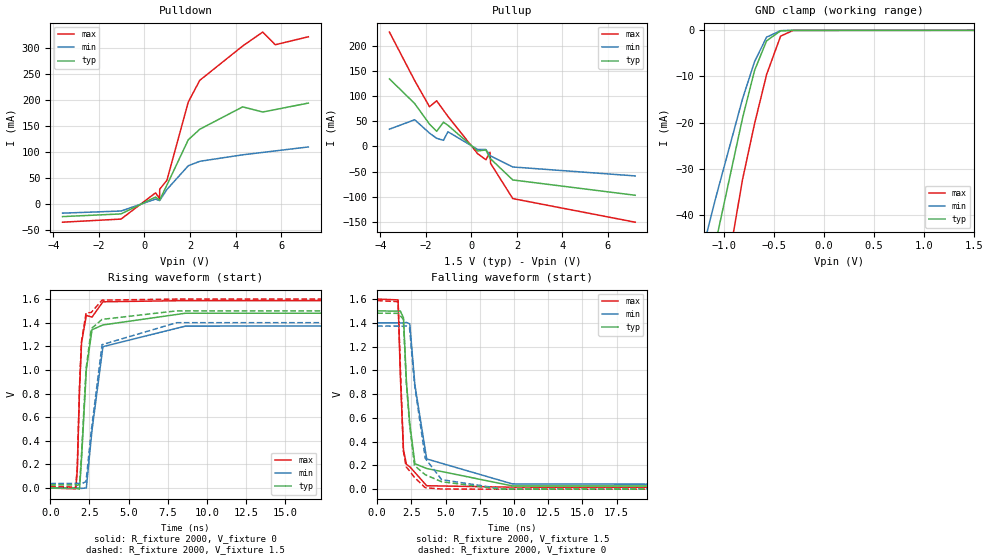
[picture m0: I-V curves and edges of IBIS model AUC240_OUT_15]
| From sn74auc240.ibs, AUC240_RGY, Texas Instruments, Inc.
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[Model]   AUC240_OUT_15
Model_type  3-state
Enable   Active-Low
Vref =   0
Rref =   2000
Cref =   15p
Vmeas =   0.75
| variable   typ   min   max
C_comp   5.73pF   5.19pF   6.05pF
| C_pullup   5.15pF   0.68pF   12.48pF
| C_pulldown   6.58pF   5.58pF   11.69pF
| C_tri-state   5.73pF   5.19pF   6.05pF
[Temperature Range]   40   100   -40
| Ambient temperature   25   85   -40
[Voltage range]   1.5   1.4   1.6
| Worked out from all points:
|   slope of the pulldown table from 0 to 0.225 V, typ, clamps not added: 37.2 ohm
|   slope of the pullup table from 0 to 0.225 V, typ, clamps not added: 29.7 ohm
|   GND clamp passes 1 mA (typ) near -0.53 V on its own axis
|   rising waveform, R_fixture 2000, V_fixture 0: 20-80 % time 420ps typ, 646ps min, 261ps max; typ from 0 V to 1.48 V
|   falling waveform, R_fixture 2000, V_fixture 1.5: 20-80 % time 551ps typ, 877ps min, 302ps max; typ from 1.5 V to 0.027 V
|   rising waveform, R_fixture 2000, V_fixture 1.5: 20-80 % time 416ps typ, 640ps min, 257ps max; typ from 0.027 V to 1.5 V
|   falling waveform, R_fixture 2000, V_fixture 0: 20-80 % time 548ps typ, 874ps min, 298ps max; typ from 1.48 V to 0 V
[GND Clamp]
| AUC240_OUT_15
|   Voltage   I(typ)   I(min)   I(max)
-3.6V     -319.1mA   -267.5mA   -389.1mA
-1.465V   -86.56mA   -69.57mA   -115.8mA
-1.33V    -72.07mA   -57.62mA   -98.32mA
-1.29V    -67.79mA   -54.11mA   -93.12mA
-1.125V   -50.33mA   -39.87mA   -71.67mA
-1.075V   -45.1mA    -35.64mA   -65.18mA
-815mV    -18.99mA   -14.82mA   -32.28mA
-695mV    -8.67mA    -6.76mA    -20.21mA
-575mV    -2.27mA    -1.475mA   -9.572mA
-435mV    -119.4uA   -67.11uA   -1.249mA
-310mV    -3.104uA   -3.768uA   -25uA
1.5V      550.3pA    10.34nA    531.3pA
[Pulldown]
| AUC240_OUT_15
|   Voltage   I(typ)   I(min)   I(max)
-3.6V     -23.87mA   -17.26mA   -34.61mA
-1.03V    -18.71mA   -13.15mA   -28.63mA
485mV     13.68mA    9.737mA    21.72mA
660mV     8.179mA    6.945mA    10.96mA
670mV     8.318mA    7.09mA     28.79mA
985mV     36.64mA    28.23mA    45.9mA
1.925V    123.7mA    73.77mA    196.2mA
2.43V     143.9mA    82.33mA    237.9mA
4.315V    186.9mA    94.81mA    303.8mA
5.195V    177mA      99.37mA    330.5mA
5.745V    181.6mA    102.3mA    306.2mA
7.2V      194.2mA    109.9mA    321.5mA
[Pullup]
| AUC240_OUT_15
|   Voltage   I(typ)   I(min)   I(max)
-3.6V     133.9mA    34.19mA    226.6mA
-2.49V    84.93mA    52.91mA    130.4mA
-1.84V    44.23mA    26.42mA    78.7mA
-1.525V   29.94mA    16.1mA     90.45mA
-1.225V   48.04mA    12.14mA    71.67mA
-1.03V    41.9mA     29.08mA    59.59mA
275mV     -9.031mA   -5.857mA   -14.38mA
640mV     -6.934mA   -6.164mA   -26.37mA
820mV     -23.64mA   -17.98mA   -11.49mA
845mV     -24.58mA   -18.83mA   -33.67mA
1.82V     -66.39mA   -40.69mA   -103.3mA
7.2V      -96.74mA   -58.4mA    -150.1mA
[Ramp]
| AUC240_OUT_15
| variable   typ   min   max
dV/dt_r   0.90/4.24E-10   0.83/6.52E-10   0.96/2.63E-10
dV/dt_f   0.89/5.52E-10   0.82/8.81E-10   0.95/3.04E-10
R_load = 2000
[Rising Waveform]
| AUC240_OUT_15
R_fixture =   2000
C_fixture =   0
L_fixture =   0
V_fixture =   0
V_fixture_min = 0
V_fixture_max = 0
|   Time   V(typ)   V(min)   V(max)
0s        9.799nV    37.61nV    995.6pV
1.63ns    348uV      750uV      -6.097mV
1.725ns   -4.351mV   989uV      146.6mV
1.87ns    -9.064mV   990.7uV    839.5mV
2ns       254.7mV    -2.694mV   1.232V
2.305ns   1.003V     1.676mV    1.462V
2.665ns   1.34V      487.4mV    1.447V
3.365ns   1.381V     1.197V     1.577V
8.64ns    1.48V      1.371V     1.587V
34.99ns   1.481V     1.373V     1.587V
[Falling Waveform]
| AUC240_OUT_15
R_fixture =   2000
C_fixture =   0
L_fixture =   0
V_fixture =   1.5
V_fixture_min = 1.4
V_fixture_max = 1.6
|   Time   V(typ)   V(min)   V(max)
0s        1.5V       1.4V       1.6V
1.53ns    1.499V     1.4V       1.593V
1.69ns    1.5V       1.399V     969.3mV
1.925ns   1.442V     1.399V     328mV
2.14ns    901.9mV    1.403V     209.2mV
2.385ns   550mV      1.391V     188.1mV
2.76ns    213.9mV    876.1mV    140.6mV
3.62ns    174mV      254.4mV    28.93mV
9.88ns    27.55mV    44.3mV     16.5mV
34.99ns   27.21mV    38.76mV    16.42mV
[Rising Waveform]
| AUC240_OUT_15
R_fixture =   2000
C_fixture =   0
L_fixture =   0
V_fixture =   1.5
V_fixture_min = 1.4
V_fixture_max = 1.6
|   Time   V(typ)   V(min)   V(max)
0s        27.17mV    38.75mV    16.4mV
1.625ns   27.61mV    39.42mV    7.834mV
1.725ns   23.28mV    39.64mV    173.2mV
1.875ns   32.96mV    39.57mV    885.5mV
1.99ns    268.8mV    36.84mV    1.236V
2.285ns   1.005V     54.82mV    1.482V
2.62ns    1.349V     484.3mV    1.487V
3.31ns    1.428V     1.214V     1.591V
8.07ns    1.5V       1.4V       1.6V
34.99ns   1.5V       1.4V       1.6V
[Falling Waveform]
| AUC240_OUT_15
R_fixture =   2000
C_fixture =   0
L_fixture =   0
V_fixture =   0
V_fixture_min = 0
V_fixture_max = 0
|   Time   V(typ)   V(min)   V(max)
0s        1.481V     1.373V     1.587V
1.53ns    1.48V      1.372V     1.578V
1.915ns   1.43V      1.371V     322.1mV
2.125ns   912.7mV    1.374V     186.9mV
2.365ns   549.6mV    1.361V     154.3mV
2.73ns    198.6mV    885.2mV    99.08mV
3.515ns   121.6mV    259.4mV    12.24mV
4.715ns   62.34mV    79.85mV    1.182mV
8.97ns    445.1uV    6.101mV    117uV
34.99ns   39.56uV    5.093uV    17.41uV
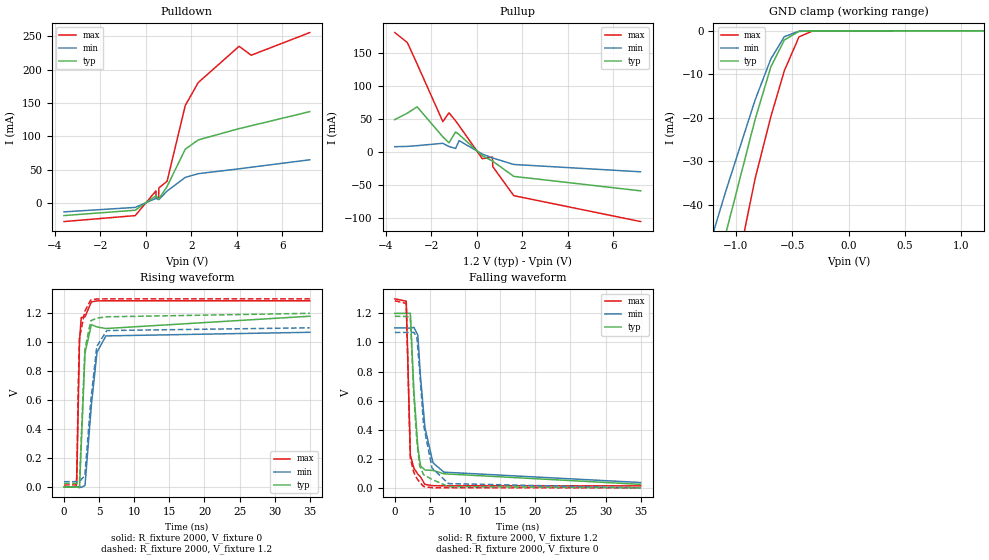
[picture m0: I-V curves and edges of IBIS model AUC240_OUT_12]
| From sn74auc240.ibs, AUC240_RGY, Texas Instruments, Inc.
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[Model]   AUC240_OUT_12
Model_type  3-state
Enable   Active-Low
Vref =   0
Rref =   2000
Cref =   15p
Vmeas =   0.6
| variable   typ   min   max
C_comp   5.84pF   5.33pF   6.15pF
| C_pullup   5.07pF   0.36pF   9.98pF
| C_pulldown   6.41pF   5.70pF   7.44pF
| C_tri-state   5.84pF   5.33pF   6.15pF
[Temperature Range]   40   100   -40
| Ambient temperature   25   85   -40
[Voltage range]   1.2   1.1   1.3
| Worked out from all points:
|   slope of the pulldown table from 0 to 0.18 V, typ, clamps not added: 42.1 ohm
|   slope of the pullup table from 0 to 0.18 V, typ, clamps not added: 38.3 ohm
|   GND clamp passes 1 mA (typ) near -0.53 V on its own axis
|   rising waveform, R_fixture 2000, V_fixture 0: 20-80 % time 597ps typ, 1.03ns min, 338ps max; typ from 0 V to 1.18 V
|   falling waveform, R_fixture 2000, V_fixture 1.2: 20-80 % time 874ps typ, 1.39ns min, 427ps max; typ from 1.2 V to 0.024 V
|   rising waveform, R_fixture 2000, V_fixture 1.2: 20-80 % time 590ps typ, 1.03ns min, 330ps max; typ from 0.024 V to 1.2 V
|   falling waveform, R_fixture 2000, V_fixture 0: 20-80 % time 864ps typ, 1.31ns min, 422ps max; typ from 1.18 V to 0 V
[GND Clamp]
| AUC240_OUT_12
|   Voltage   I(typ)   I(min)   I(max)
-3.6V     -319.1mA   -267.5mA   -389.1mA
-1.46V    -86.02mA   -69.12mA   -115.2mA
-1.415V   -81.18mA   -65.12mA   -109.4mA
-1.285V   -67.26mA   -53.68mA   -92.47mA
-1.12V    -49.8mA    -39.44mA   -71.02mA
-1.085V   -46.14mA   -36.48mA   -66.48mA
-830mV    -20.41mA   -15.93mA   -34.03mA
-690mV    -8.305mA   -6.469mA   -19.75mA
-570mV    -2.106mA   -1.347mA   -9.166mA
-440mV    -136.2uA   -75.22uA   -1.399mA
-320mV    -4.216uA   -4.87uA    -36.5uA
1.2V      442.5pA    10.22nA    378.9pA
[Pulldown]
| AUC240_OUT_12
|   Voltage   I(typ)   I(min)   I(max)
-3.6V     -19.18mA   -13.63mA   -28.17mA
-470mV    -11.13mA   -6.91mA    -19.23mA
440mV     10.48mA    6.706mA    17.92mA
445mV     10.59mA    6.769mA    6.318mA
560mV     5.857mA    4.698mA    8.209mA
570mV     5.97mA     4.785mA    22.41mA
930mV     24.61mA    17.66mA    32.37mA
1.73V     80.53mA    38.18mA    146.2mA
2.3V      94.46mA    43.74mA    180.6mA
4.095V    111.4mA    51.05mA    235mA
4.625V    115.7mA    53.39mA    221.6mA
7.2V      136.9mA    64.6mA     255.6mA
[Pullup]
| AUC240_OUT_12
|   Voltage   I(typ)   I(min)   I(max)
-3.6V     48.8mA     7.73mA     180.5mA
-3.05V    58.5mA     8.2mA      165.4mA
-2.62V    68.11mA    9.305mA    132.9mA
-1.49V    22.6mA     12.87mA    45.69mA
-1.22V    13.65mA    7.955mA    59.11mA
-930mV    30.05mA    5.089mA    46.94mA
-775mV    26.1mA     16.83mA    39.5mA
245mV     -5.916mA   -3.381mA   -10.43mA
690mV     -14.05mA   -9.318mA   -7.997mA
705mV     -14.25mA   -9.471mA   -22.45mA
1.625V    -37.2mA    -19.16mA   -66.38mA
7.2V      -59.1mA    -30.27mA   -105.6mA
[Ramp]
| AUC240_OUT_12
| variable   typ   min   max
dV/dt_r   0.72/6.03E-10   0.65/1.04E-09   0.78/3.41E-10
dV/dt_f   0.71/8.77E-10   0.64/1.39E-09   0.77/4.32E-10
R_load = 2000
[Rising Waveform]
| AUC240_OUT_12
R_fixture =   2000
C_fixture =   0
L_fixture =   0
V_fixture =   0
V_fixture_min = 0
V_fixture_max = 0
|   Time   V(typ)   V(min)   V(max)
0s        9.189nV    39.93nV    791.2pV
1.75ns    708.7uV    366uV      924.3uV
1.825ns   798.9uV    495uV      60.17mV
2.21ns    -6.059mV   1.444mV    1.01V
2.46ns    292.5mV    -3.387mV   1.17V
2.995ns   927.4mV    10.9mV     1.177V
3.9ns     1.122V     565.9mV    1.279V
4.7ns     1.106V     931.1mV    1.286V
5.97ns    1.095V     1.044V     1.287V
34.99ns   1.18V      1.069V     1.287V
[Falling Waveform]
| AUC240_OUT_12
R_fixture =   2000
C_fixture =   0
L_fixture =   0
V_fixture =   1.2
V_fixture_min = 1.1
V_fixture_max = 1.3
|   Time   V(typ)   V(min)   V(max)
0s        1.2V       1.1V       1.3V
1.625ns   1.2V       1.1V       1.284V
2.21ns    1.201V     1.099V     224.4mV
2.72ns    657.1mV    1.104V     135.1mV
3.275ns   283.2mV    1.05V      94.28mV
3.655ns   150.9mV    765.8mV    75.21mV
4.285ns   122.8mV    415.8mV    23.41mV
5.43ns    120.1mV    172.2mV    14.94mV
6.99ns    96.77mV    108mV      14.16mV
34.99ns   24.03mV    36.64mV    13.88mV
[Rising Waveform]
| AUC240_OUT_12
R_fixture =   2000
C_fixture =   0
L_fixture =   0
V_fixture =   1.2
V_fixture_min = 1.1
V_fixture_max = 1.3
|   Time   V(typ)   V(min)   V(max)
0s        23.98mV    36.61mV    13.86mV
1.745ns   24.6mV     36.92mV    14.73mV
1.825ns   24.68mV    37.03mV    83.81mV
2.025ns   19.36mV    37.36mV    683.6mV
2.205ns   33.36mV    37.7mV     1.03V
2.97ns    949.2mV    78.55mV    1.215V
3.82ns    1.149V     596mV      1.293V
4.665ns   1.167V     972mV      1.299V
6.095ns   1.176V     1.081V     1.3V
34.99ns   1.2V       1.1V       1.3V
[Falling Waveform]
| AUC240_OUT_12
R_fixture =   2000
C_fixture =   0
L_fixture =   0
V_fixture =   0
V_fixture_min = 0
V_fixture_max = 0
|   Time   V(typ)   V(min)   V(max)
0s        1.18V      1.069V     1.287V
1.625ns   1.179V     1.069V     1.269V
2.21ns    1.174V     1.068V     203.6mV
2.7ns     636.7mV    1.07V      106.9mV
3.14ns    320.6mV    1.036V     64.66mV
3.535ns   152.1mV    804.4mV    39.08mV
4.09ns    90.67mV    431.9mV    9.619mV
5.3ns     57.97mV    136mV      954.3uV
7.63ns    8.494mV    29.25mV    204uV
34.99ns   50.42uV    12.36uV    18.72uV
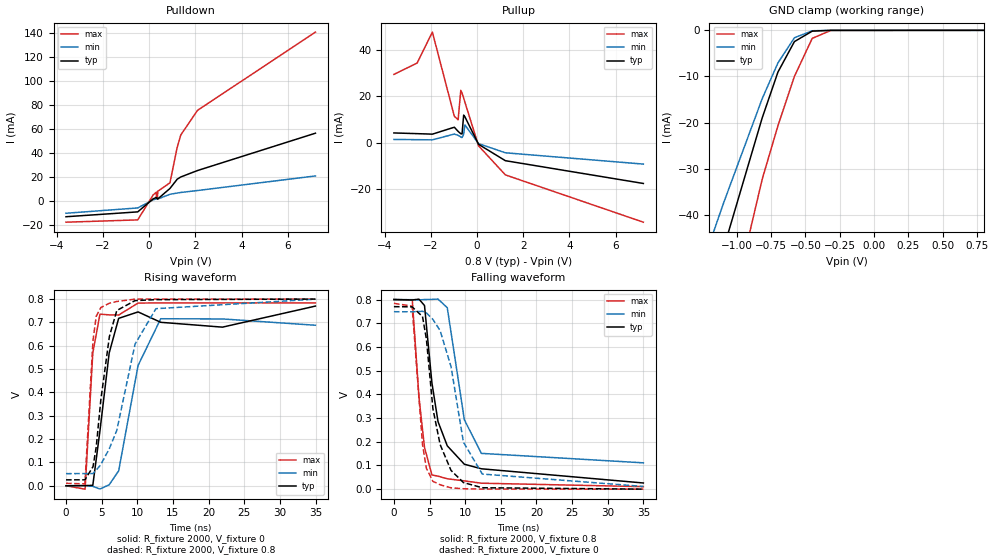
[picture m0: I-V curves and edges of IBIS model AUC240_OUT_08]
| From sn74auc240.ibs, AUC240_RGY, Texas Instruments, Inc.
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[Model]   AUC240_OUT_08
Model_type  3-state
Enable   Active-Low
Vref =   0
Rref =   2000
Cref =   15p
Vmeas =   0.4
| variable   typ   min   max
C_comp   5.94pF   5.47pF   6.22pF
| C_pullup   6.11pF   1.57pF   8.48pF
| C_pulldown   6.55pF   5.99pF   7.01pF
| C_tri-state   5.94pF   5.47pF   6.22pF
[Temperature Range]   40   100   -40
| Ambient temperature   25   85   -40
[Voltage range]   0.8   0.8   0.8
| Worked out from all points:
|   slope of the pulldown table from 0 to 0.12 V, typ, clamps not added: 77.5 ohm
|   slope of the pullup table from 0 to 0.12 V, typ, clamps not added: 92.9 ohm
|   GND clamp passes 1 mA (typ) near -0.53 V on its own axis
|   rising waveform, R_fixture 2000, V_fixture 0: 20-80 % time 1.81ns typ, 2.48ns min, 953ps max; typ from 0 V to 0.77 V
|   falling waveform, R_fixture 2000, V_fixture 0.8: 20-80 % time 2.72ns typ, 2.13ns min, 1.39ns max; typ from 0.8 V to 0.026 V
|   rising waveform, R_fixture 2000, V_fixture 0.8: 20-80 % time 1.83ns typ, 3.54ns min, 902ps max; typ from 0.025 V to 0.8 V
|   falling waveform, R_fixture 2000, V_fixture 0: 20-80 % time 2.24ns typ, 2.81ns min, 1.25ns max; typ from 0.77 V to 0 V
[GND Clamp]
| AUC240_OUT_08
|   Voltage   I(typ)   I(min)   I(max)
-3.6V     -319.1mA   -267.5mA   -389.1mA
-1.475V   -87.64mA   -70.46mA   -117.1mA
-1.34V    -73.14mA   -58.5mA    -99.62mA
-1.295V   -68.33mA   -54.55mA   -93.77mA
-1.125V   -50.33mA   -39.87mA   -71.67mA
-1.09V    -46.66mA   -36.9mA    -67.13mA
-815mV    -18.99mA   -14.82mA   -32.28mA
-700mV    -9.043mA   -7.055mA   -20.67mA
-580mV    -2.441mA   -1.611mA   -9.983mA
-450mV    -176.4uA   -94.71uA   -1.735mA
-315mV    -3.617uA   -4.287uA   -30.24uA
800mV     320.2pA    582.3pA    244.9pA
[Pulldown]
| AUC240_OUT_08
|   Voltage   I(typ)   I(min)   I(max)
-3.6V     -12.84mA   -9.953mA   -17.38mA
-495mV    -8.803mA   -5.523mA   -15.47mA
175mV     2.059mA    1.185mA    5.31mA
310mV     3.174mA    2.053mA    7.502mA
315mV     3.217mA    2.087mA    2.47mA
365mV     1.856mA    1.796mA    2.807mA
370mV     1.894mA    1.829mA    8.27mA
900mV     10.66mA    5.825mA    15.37mA
1.215V    18.37mA    6.848mA    44.91mA
1.37V     20.23mA    7.332mA    55.15mA
2.09V     25.55mA    8.946mA    75.56mA
7.2V      56.63mA    21.09mA    140.7mA
[Pullup]
| AUC240_OUT_08
|   Voltage   I(typ)   I(min)   I(max)
-3.6V     4.13mA     1.333mA    29.34mA
-2.595V   3.829mA    1.231mA    34.24mA
-1.935V   3.609mA    1.155mA    47.57mA
-985mV    6.593mA    3.652mA    11.35mA
-820mV    4.807mA    3.079mA    9.795mA
-705mV    3.788mA    2.41mA     22.46mA
-650mV    3.702mA    2.149mA    21.3mA
-580mV    11.83mA    3.56mA     19.16mA
-530mV    11.15mA    7.583mA    17.47mA
65mV      -779.5uA   -459.6uA   -1.427mA
1.225V    -7.819mA   -4.418mA   -13.93mA
7.2V      -17.63mA   -9.285mA   -34.31mA
[Ramp]
| AUC240_OUT_08
| variable   typ   min   max
dV/dt_r   0.47/1.82E-09   0.46/2.98E-09   0.48/9.63E-10
dV/dt_f   0.47/2.72E-09   0.42/2.15E-09   0.48/1.39E-09
R_load = 2000
[Rising Waveform]
| AUC240_OUT_08
R_fixture =   2000
C_fixture =   0
L_fixture =   0
V_fixture =   0
V_fixture_min = 0
V_fixture_max = 0
|   Time   V(typ)   V(min)   V(max)
0s        11.33nV    65.3nV     597.2pV
2.68ns    703.4uV    1.242mV    -14.52mV
3.76ns    1.948mV    -2.311mV   569.2mV
4.765ns   236.2mV    -13.84mV   735.3mV
6.06ns    569.5mV    4.391mV    732.3mV
7.39ns    717.4mV    64.1mV     731.6mV
10.11ns   744.9mV    515.4mV    782.9mV
13.29ns   700.4mV    715.7mV    783.5mV
21.95ns   679.7mV    714.8mV    783.7mV
34.99ns   769.9mV    687.8mV    783.7mV
[Falling Waveform]
| AUC240_OUT_08
R_fixture =   2000
C_fixture =   0
L_fixture =   0
V_fixture =   0.8
V_fixture_min = 0.8
V_fixture_max = 0.8
|   Time   V(typ)   V(min)   V(max)
0s        800mV      800mV      800mV
2.575ns   798.2mV    799.4mV    798.2mV
3.515ns   801.7mV    798.5mV    387.5mV
4.29ns    774.7mV    800mV      176.4mV
5.33ns    448.6mV    800.6mV    60.17mV
6.185ns   285.2mV    802mV      54.88mV
7.485ns   182.8mV    765.6mV    43.9mV
9.88ns    105.2mV    292.8mV    34.98mV
12.27ns   86.02mV    151mV      25.22mV
34.99ns   26.09mV    111.1mV    10.63mV
[Rising Waveform]
| AUC240_OUT_08
R_fixture =   2000
C_fixture =   0
L_fixture =   0
V_fixture =   0.8
V_fixture_min = 0.8
V_fixture_max = 0.8
|   Time   V(typ)   V(min)   V(max)
0s        25.46mV    51.93mV    10.6mV
2.65ns    25.51mV    52.28mV    8.255mV
3.79ns    81.68mV    52.14mV    623.5mV
4.24ns    166.4mV    67.16mV    726mV
4.885ns   368mV      90.79mV    763.7mV
6.085ns   639.3mV    159.6mV    782.1mV
7.125ns   751mV      237.5mV    789.6mV
9.68ns    793.3mV    606.6mV    799.7mV
12.62ns   797.5mV    758.8mV    799.8mV
34.99ns   799.9mV    799.5mV    800mV
[Falling Waveform]
| AUC240_OUT_08
R_fixture =   2000
C_fixture =   0
L_fixture =   0
V_fixture =   0
V_fixture_min = 0
V_fixture_max = 0
|   Time   V(typ)   V(min)   V(max)
0s        770mV      748.6mV    783.8mV
2.55ns    769.1mV    748.3mV    772.2mV
4.01ns    728.4mV    750.4mV    188.7mV
4.555ns   633.6mV    743.8mV    87.89mV
5.47ns    339.4mV    716.1mV    33.11mV
6.48ns    188.4mV    669.2mV    18.56mV
8.01ns    79.19mV    517.2mV    5.709mV
9.75ns    27.92mV    198.4mV    1.862mV
12.39ns   6.047mV    63.86mV    348.7uV
34.99ns   141.8uV    11.4mV     28.71uV
